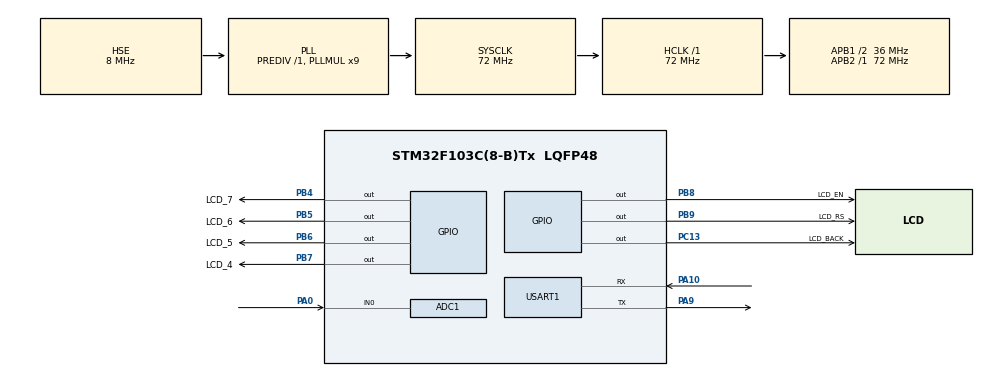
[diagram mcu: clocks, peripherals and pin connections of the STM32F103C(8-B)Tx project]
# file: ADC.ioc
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ADC1.Channel-0\#ChannelRegularConversion=ADC_CHANNEL_0
ADC1.NbrOfConversionFlag=1
ADC1.Rank-0\#ChannelRegularConversion=1
ADC1.SamplingTime-0\#ChannelRegularConversion=ADC_SAMPLETIME_1CYCLE_5
ADC1.master=1
Mcu.Family=STM32F1
Mcu.Name=STM32F103C(8-B)Tx
Mcu.Package=LQFP48
NVIC.PriorityGroup=NVIC_PRIORITYGROUP_4
NVIC.RCC_IRQn=true\:0\:0\:false\:false\:true\:true\:false\:true
PA0-WKUP.Signal=ADCx_IN0
PA10.Mode=Asynchronous
PA10.Signal=USART1_RX
PA9.Mode=Asynchronous
PA9.Signal=USART1_TX
PB4.GPIO_Label=LCD_7
PB4.Signal=GPIO_Output
PB5.GPIO_Label=LCD_6
PB5.Signal=GPIO_Output
PB6.GPIO_Label=LCD_5
PB6.Signal=GPIO_Output
PB7.GPIO_Label=LCD_4
PB7.Signal=GPIO_Output
PB8.GPIO_Label=LCD_EN
PB8.Signal=GPIO_Output
PB9.GPIO_Label=LCD_RS
PB9.Signal=GPIO_Output
PC13-TAMPER-RTC.GPIO_Label=LCD_BACK
PC13-TAMPER-RTC.Signal=GPIO_Output
PD0-OSC_IN.Mode=HSE-External-Oscillator
PD0-OSC_IN.Signal=RCC_OSC_IN
PD1-OSC_OUT.Mode=HSE-External-Oscillator
PD1-OSC_OUT.Signal=RCC_OSC_OUT
ProjectManager.HeapSize=0x200
ProjectManager.StackSize=0x400
ProjectManager.TargetToolchain=STM32CubeIDE
RCC.ADCPresc=RCC_ADCPCLK2_DIV6
RCC.AHBFreq_Value=72000000
RCC.APB1CLKDivider=RCC_HCLK_DIV2
RCC.APB1Freq_Value=36000000
RCC.APB1TimFreq_Value=72000000
RCC.APB2Freq_Value=72000000
RCC.APB2TimFreq_Value=72000000
RCC.HCLKFreq_Value=72000000
RCC.PLLMUL=RCC_PLL_MUL9
RCC.PLLSourceVirtual=RCC_PLLSOURCE_HSE
RCC.SYSCLKFreq_VALUE=72000000
RCC.SYSCLKSource=RCC_SYSCLKSOURCE_PLLCLK
RCC.USBFreq_Value=72000000
SH.ADCx_IN0.0=ADC1_IN0,IN0
USART1.VirtualMode=VM_ASYNC
VP_SYS_VS_ND.Mode=No_Debug
board=custom

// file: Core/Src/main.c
/* USER CODE BEGIN Header */
/**
  ******************************************************************************
  * @file           : main.c
  * @brief          : Main program body
  ******************************************************************************
  */

#include "main.h"
#include <stdio.h>
#include <string.h>

ADC_HandleTypeDef hadc1;
UART_HandleTypeDef huart1;

void SystemClock_Config(void);
static void MX_GPIO_Init(void);
static void MX_ADC1_Init(void);
static void MX_USART1_UART_Init(void);

/* LCD Functions */
void LCD_Enable(void);
void LCD_Send4Bits(uint8_t data);
void LCD_SendCommand(uint8_t cmd);
void LCD_SendData(uint8_t data);
void LCD_Init(void);
void LCD_SetCursor(uint8_t row, uint8_t col);
void LCD_Print(char *str);

/* USER CODE BEGIN 0 */

/* ================= LCD ENABLE ================= */

void LCD_Enable(void)
{
    HAL_GPIO_WritePin(LCD_E_GPIO_Port, LCD_E_Pin, GPIO_PIN_SET);

    HAL_Delay(1);

    HAL_GPIO_WritePin(LCD_E_GPIO_Port, LCD_E_Pin, GPIO_PIN_RESET);

    HAL_Delay(1);
}

/* ================= SEND 4 BITS ================= */

void LCD_Send4Bits(uint8_t data)
{
    HAL_GPIO_WritePin(LCD_D4_GPIO_Port,
                      LCD_D4_Pin,
                      (data & 0x01) ? GPIO_PIN_SET : GPIO_PIN_RESET);

    HAL_GPIO_WritePin(LCD_D5_GPIO_Port,
                      LCD_D5_Pin,
                      (data & 0x02) ? GPIO_PIN_SET : GPIO_PIN_RESET);

    HAL_GPIO_WritePin(LCD_D6_GPIO_Port,
                      LCD_D6_Pin,
                      (data & 0x04) ? GPIO_PIN_SET : GPIO_PIN_RESET);

    HAL_GPIO_WritePin(LCD_D7_GPIO_Port,
                      LCD_D7_Pin,
                      (data & 0x08) ? GPIO_PIN_SET : GPIO_PIN_RESET);

    LCD_Enable();
}

/* ================= SEND COMMAND ================= */

void LCD_SendCommand(uint8_t cmd)
{
    /* RS = 0 for command */

    HAL_GPIO_WritePin(LCD_RS_GPIO_Port,
                      LCD_RS_Pin,
                      GPIO_PIN_RESET);

    LCD_Send4Bits(cmd >> 4);

    LCD_Send4Bits(cmd & 0x0F);

    HAL_Delay(2);
}

/* ================= SEND DATA ================= */

void LCD_SendData(uint8_t data)
{
    /* RS = 1 for data */

    HAL_GPIO_WritePin(LCD_RS_GPIO_Port,
                      LCD_RS_Pin,
                      GPIO_PIN_SET);

    LCD_Send4Bits(data >> 4);

    LCD_Send4Bits(data & 0x0F);

    HAL_Delay(1);
}

/* ================= LCD INITIALIZATION ================= */

void LCD_Init(void)
{
    HAL_Delay(20);

    HAL_GPIO_WritePin(LCD_RS_GPIO_Port,
                      LCD_RS_Pin,
                      GPIO_PIN_RESET);

    /* Initialization sequence */

    LCD_Send4Bits(0x03);
    HAL_Delay(5);

    LCD_Send4Bits(0x03);
    HAL_Delay(1);

    LCD_Send4Bits(0x03);
    HAL_Delay(1);

    LCD_Send4Bits(0x02);

    /* 4-bit mode, 2 lines, 5x8 font */
    LCD_SendCommand(0x28);

    /* Display ON, cursor OFF */
    LCD_SendCommand(0x0C);

    /* Entry mode */
    LCD_SendCommand(0x06);

    /* Clear display */
    LCD_SendCommand(0x01);

    HAL_Delay(2);
}

/* ================= LCD CURSOR ================= */

void LCD_SetCursor(uint8_t row, uint8_t col)
{
    uint8_t address;

    if (row == 0)
    {
        address = 0x80 + col;
    }
    else
    {
        address = 0xC0 + col;
    }

    LCD_SendCommand(address);
}

/* ================= LCD PRINT ================= */

void LCD_Print(char *str)
{
    while (*str)
    {
        LCD_SendData(*str);
        str++;
    }
}

/* USER CODE END 0 */

int main(void)
{
    /* USER CODE BEGIN 1 */

    int a;

    char str[50];

    char lcd_str[17];

    float v;

    /* USER CODE END 1 */

    /* MCU Configuration */

    HAL_Init();

    /* Configure system clock */

    SystemClock_Config();

    /* Initialize peripherals */

    MX_GPIO_Init();

    MX_ADC1_Init();

    MX_USART1_UART_Init();

    /* USER CODE BEGIN 2 */

    /* ADC Calibration */

    HAL_ADCEx_Calibration_Start(&hadc1);

    /* LCD Initialization */

    LCD_Init();

    /* LCD Backlight ON */

    HAL_GPIO_WritePin(GPIOC,
                      GPIO_PIN_13,
                      GPIO_PIN_SET);

    /* Startup message */

    LCD_SetCursor(0, 0);

    LCD_Print("ADC VOLTAGE");

    LCD_SetCursor(1, 0);

    LCD_Print("Initializing...");

    HAL_Delay(1000);

    LCD_SendCommand(0x01);

    /* USER CODE END 2 */

    /* Infinite loop */

    while (1)
    {
        /* ================= ADC START ================= */

        HAL_ADC_Start(&hadc1);

        /* Wait for conversion */

        HAL_ADC_PollForConversion(&hadc1, 10);

        /* Get ADC value */

        a = HAL_ADC_GetValue(&hadc1);

        /* ================= VOLTAGE ================= */

        /*
         * 12-bit ADC
         *
         * ADC range = 0 to 4095
         *
         * Reference = 3.3V
         */

        v = (a * 3.3f) / 4095.0f;

        /* ================= UART ================= */

        sprintf(str,
                "RAW:%d Volts: %.2f\r\n",
                a,
                v);

        HAL_UART_Transmit(&huart1,
                          (uint8_t *)str,
                          strlen(str),
                          500);

        /* ================= LCD LINE 1 ================= */

        LCD_SetCursor(0, 0);

        sprintf(lcd_str,
                "RAW: %4d       ",
                a);

        LCD_Print(lcd_str);

        /* ================= LCD LINE 2 ================= */

        LCD_SetCursor(1, 0);

        sprintf(lcd_str,
                "VOLT: %.2f V     ",
                v);

        LCD_Print(lcd_str);

        /* Update every 1 second */

        HAL_Delay(1000);
    }
}

void SystemClock_Config(void)
{
    RCC_OscInitTypeDef RCC_OscInitStruct = {0};

    RCC_ClkInitTypeDef RCC_ClkInitStruct = {0};

    RCC_PeriphCLKInitTypeDef PeriphClkInit = {0};

    /* Oscillator configuration */

    RCC_OscInitStruct.OscillatorType =
        RCC_OSCILLATORTYPE_HSE;

    RCC_OscInitStruct.HSEState =
        RCC_HSE_ON;

    RCC_OscInitStruct.HSEPredivValue =
        RCC_HSE_PREDIV_DIV1;

    RCC_OscInitStruct.HSIState =
        RCC_HSI_ON;

    RCC_OscInitStruct.PLL.PLLState =
        RCC_PLL_ON;

    RCC_OscInitStruct.PLL.PLLSource =
        RCC_PLLSOURCE_HSE;

    RCC_OscInitStruct.PLL.PLLMUL =
        RCC_PLL_MUL9;

    if (HAL_RCC_OscConfig(&RCC_OscInitStruct) != HAL_OK)
    {
        Error_Handler();
    }

    /* Clock configuration */

    RCC_ClkInitStruct.ClockType =
        RCC_CLOCKTYPE_HCLK |
        RCC_CLOCKTYPE_SYSCLK |
        RCC_CLOCKTYPE_PCLK1 |
        RCC_CLOCKTYPE_PCLK2;

    RCC_ClkInitStruct.SYSCLKSource =
        RCC_SYSCLKSOURCE_PLLCLK;

    RCC_ClkInitStruct.AHBCLKDivider =
        RCC_SYSCLK_DIV1;

    RCC_ClkInitStruct.APB1CLKDivider =
        RCC_HCLK_DIV2;

    RCC_ClkInitStruct.APB2CLKDivider =
        RCC_HCLK_DIV1;

    if (HAL_RCC_ClockConfig(&RCC_ClkInitStruct,
                            FLASH_LATENCY_2) != HAL_OK)
    {
        Error_Handler();
    }

    /* ADC clock */

    PeriphClkInit.PeriphClockSelection =
        RCC_PERIPHCLK_ADC;

    PeriphClkInit.AdcClockSelection =
        RCC_ADCPCLK2_DIV6;

    if (HAL_RCCEx_PeriphCLKConfig(&PeriphClkInit) != HAL_OK)
    {
        Error_Handler();
    }
}

static void MX_ADC1_Init(void)
{
    ADC_ChannelConfTypeDef sConfig = {0};

    hadc1.Instance = ADC1;

    hadc1.Init.ScanConvMode =
        ADC_SCAN_DISABLE;

    hadc1.Init.ContinuousConvMode =
        DISABLE;

    hadc1.Init.DiscontinuousConvMode =
        DISABLE;

    hadc1.Init.ExternalTrigConv =
        ADC_SOFTWARE_START;

    hadc1.Init.DataAlign =
        ADC_DATAALIGN_RIGHT;

    hadc1.Init.NbrOfConversion =
        1;

    if (HAL_ADC_Init(&hadc1) != HAL_OK)
    {
        Error_Handler();
    }

    /* ADC Channel 0 = PA0 */

    sConfig.Channel =
        ADC_CHANNEL_0;

    sConfig.Rank =
        ADC_REGULAR_RANK_1;

    sConfig.SamplingTime =
        ADC_SAMPLETIME_1CYCLE_5;

    if (HAL_ADC_ConfigChannel(&hadc1,
                              &sConfig) != HAL_OK)
    {
        Error_Handler();
    }
}

static void MX_USART1_UART_Init(void)
{
    huart1.Instance = USART1;

    huart1.Init.BaudRate =
        115200;

    huart1.Init.WordLength =
        UART_WORDLENGTH_8B;

    huart1.Init.StopBits =
        UART_STOPBITS_1;

    huart1.Init.Parity =
        UART_PARITY_NONE;

    huart1.Init.Mode =
        UART_MODE_TX_RX;

    huart1.Init.HwFlowCtl =
        UART_HWCONTROL_NONE;

    huart1.Init.OverSampling =
        UART_OVERSAMPLING_16;

    if (HAL_UART_Init(&huart1) != HAL_OK)
    {
        Error_Handler();
    }
}

static void MX_GPIO_Init(void)
{
    GPIO_InitTypeDef GPIO_InitStruct = {0};

    /* ================= GPIO CLOCK ENABLE ================= */

    __HAL_RCC_GPIOD_CLK_ENABLE();

    __HAL_RCC_GPIOA_CLK_ENABLE();

    __HAL_RCC_GPIOB_CLK_ENABLE();

    __HAL_RCC_GPIOC_CLK_ENABLE();

    /* ================= LCD INITIAL OUTPUT ================= */

    HAL_GPIO_WritePin(
        GPIOB,
        LCD_D7_Pin |
        LCD_D6_Pin |
        LCD_D5_Pin |
        LCD_D4_Pin |
        LCD_E_Pin |
        LCD_RS_Pin,
        GPIO_PIN_RESET
    );

    /* ================= LCD GPIO CONFIGURATION ================= */

    GPIO_InitStruct.Pin =
        LCD_D7_Pin |
        LCD_D6_Pin |
        LCD_D5_Pin |
        LCD_D4_Pin |
        LCD_E_Pin |
        LCD_RS_Pin;

    GPIO_InitStruct.Mode =
        GPIO_MODE_OUTPUT_PP;

    GPIO_InitStruct.Pull =
        GPIO_NOPULL;

    GPIO_InitStruct.Speed =
        GPIO_SPEED_FREQ_LOW;

    HAL_GPIO_Init(GPIOB,
                  &GPIO_InitStruct);

    /* ================= PC13 BACKLIGHT ================= */

    GPIO_InitStruct.Pin =
        GPIO_PIN_13;

    GPIO_InitStruct.Mode =
        GPIO_MODE_OUTPUT_PP;

    GPIO_InitStruct.Pull =
        GPIO_NOPULL;

    GPIO_InitStruct.Speed =
        GPIO_SPEED_FREQ_LOW;

    HAL_GPIO_Init(GPIOC,
                  &GPIO_InitStruct);

    /* Backlight ON */

    HAL_GPIO_WritePin(GPIOC,
                      GPIO_PIN_13,
                      GPIO_PIN_SET);
}

/**
  * @brief Error Handler
  */

void Error_Handler(void)
{
    __disable_irq();

    while (1)
    {
    }
}
